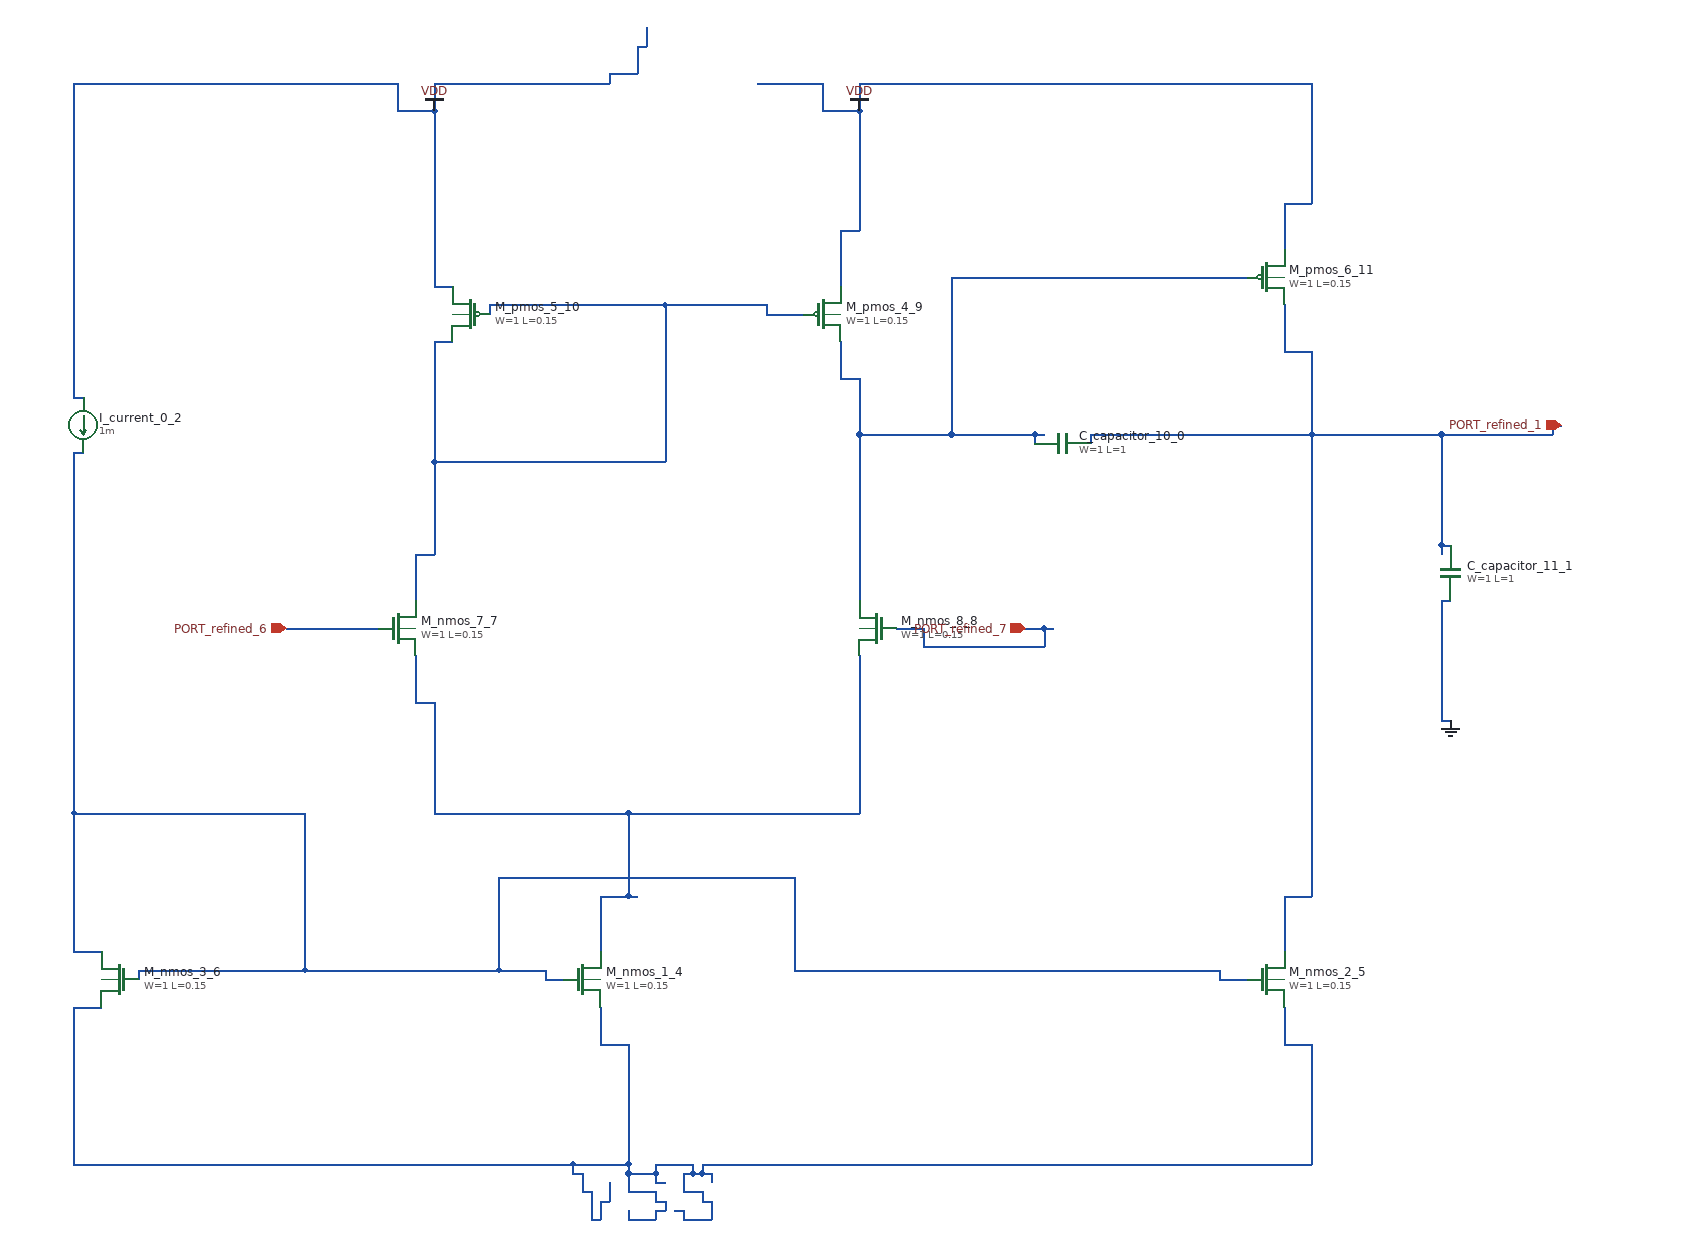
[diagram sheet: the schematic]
v {xschem version=3.4.8 file_version=1.2}
G {}
K {}
V {}
S {}
E {}
C {sky130_fd_pr/cap_mim_m3_1.sym} 1200 500 1 0 {name="C_capacitor_10_0" model=cap_mim_m3_1 W=1 L=1 MF=1 spiceprefix=X}
C {sky130_fd_pr/cap_mim_m3_1.sym} 1620 640 2 0 {name="C_capacitor_11_1" model=cap_mim_m3_1 W=1 L=1 MF=1 spiceprefix=X}
C {devices/isource.sym} 140 480 0 0 {name="I_current_0_2" value=1m}
C {devices/gnd.sym} 1620 800 0 0 {name="l_gnd_9_3" lab="GND"}
C {sky130_fd_pr/nfet3_01v8.sym} 680 1080 0 0 {name="M_nmos_1_4"
W=1
L=0.15
body=GND
nf=1
mult=1
ad="expr('int((@nf + 1)/2) * @W / @nf * 0.29')"
pd="expr('2*int((@nf + 1)/2) * (@W / @nf + 0.29)')"
as="expr('int((@nf + 2)/2) * @W / @nf * 0.29')"
ps="expr('2*int((@nf + 2)/2) * (@W / @nf + 0.29)')"
nrd="expr('0.29 / @W ')" nrs="expr('0.29 / @W ')"
sa=0 sb=0 sd=0
model=nfet_01v8
spiceprefix=X
}
C {sky130_fd_pr/nfet3_01v8.sym} 1420 1080 0 0 {name="M_nmos_2_5"
W=1
L=0.15
body=GND
nf=1
mult=1
ad="expr('int((@nf + 1)/2) * @W / @nf * 0.29')"
pd="expr('2*int((@nf + 1)/2) * (@W / @nf + 0.29)')"
as="expr('int((@nf + 2)/2) * @W / @nf * 0.29')"
ps="expr('2*int((@nf + 2)/2) * (@W / @nf + 0.29)')"
nrd="expr('0.29 / @W ')" nrs="expr('0.29 / @W ')"
sa=0 sb=0 sd=0
model=nfet_01v8
spiceprefix=X
}
C {sky130_fd_pr/nfet3_01v8.sym} 180 1080 0 1 {name="M_nmos_3_6"
W=1
L=0.15
body=GND
nf=1
mult=1
ad="expr('int((@nf + 1)/2) * @W / @nf * 0.29')"
pd="expr('2*int((@nf + 1)/2) * (@W / @nf + 0.29)')"
as="expr('int((@nf + 2)/2) * @W / @nf * 0.29')"
ps="expr('2*int((@nf + 2)/2) * (@W / @nf + 0.29)')"
nrd="expr('0.29 / @W ')" nrs="expr('0.29 / @W ')"
sa=0 sb=0 sd=0
model=nfet_01v8
spiceprefix=X
}
C {sky130_fd_pr/nfet3_01v8.sym} 480 700 0 0 {name="M_nmos_7_7"
W=1
L=0.15
body=GND
nf=1
mult=1
ad="expr('int((@nf + 1)/2) * @W / @nf * 0.29')"
pd="expr('2*int((@nf + 1)/2) * (@W / @nf + 0.29)')"
as="expr('int((@nf + 2)/2) * @W / @nf * 0.29')"
ps="expr('2*int((@nf + 2)/2) * (@W / @nf + 0.29)')"
nrd="expr('0.29 / @W ')" nrs="expr('0.29 / @W ')"
sa=0 sb=0 sd=0
model=nfet_01v8
spiceprefix=X
}
C {sky130_fd_pr/nfet3_01v8.sym} 1000 700 0 1 {name="M_nmos_8_8"
W=1
L=0.15
body=GND
nf=1
mult=1
ad="expr('int((@nf + 1)/2) * @W / @nf * 0.29')"
pd="expr('2*int((@nf + 1)/2) * (@W / @nf + 0.29)')"
as="expr('int((@nf + 2)/2) * @W / @nf * 0.29')"
ps="expr('2*int((@nf + 2)/2) * (@W / @nf + 0.29)')"
nrd="expr('0.29 / @W ')" nrs="expr('0.29 / @W ')"
sa=0 sb=0 sd=0
model=nfet_01v8
spiceprefix=X
}
C {sky130_fd_pr/pfet3_01v8.sym} 940 360 0 0 {name="M_pmos_4_9"
W=1
L=0.15
body=VDD
nf=1
mult=1
ad="expr('int((@nf + 1)/2) * @W / @nf * 0.29')"
pd="expr('2*int((@nf + 1)/2) * (@W / @nf + 0.29)')"
as="expr('int((@nf + 2)/2) * @W / @nf * 0.29')"
ps="expr('2*int((@nf + 2)/2) * (@W / @nf + 0.29)')"
nrd="expr('0.29 / @W ')" nrs="expr('0.29 / @W ')"
sa=0 sb=0 sd=0
model=pfet_01v8
spiceprefix=X
}
C {sky130_fd_pr/pfet3_01v8.sym} 560 360 0 1 {name="M_pmos_5_10"
W=1
L=0.15
body=VDD
nf=1
mult=1
ad="expr('int((@nf + 1)/2) * @W / @nf * 0.29')"
pd="expr('2*int((@nf + 1)/2) * (@W / @nf + 0.29)')"
as="expr('int((@nf + 2)/2) * @W / @nf * 0.29')"
ps="expr('2*int((@nf + 2)/2) * (@W / @nf + 0.29)')"
nrd="expr('0.29 / @W ')" nrs="expr('0.29 / @W ')"
sa=0 sb=0 sd=0
model=pfet_01v8
spiceprefix=X
}
C {sky130_fd_pr/pfet3_01v8.sym} 1420 320 0 0 {name="M_pmos_6_11"
W=1
L=0.15
body=VDD
nf=1
mult=1
ad="expr('int((@nf + 1)/2) * @W / @nf * 0.29')"
pd="expr('2*int((@nf + 1)/2) * (@W / @nf + 0.29)')"
as="expr('int((@nf + 2)/2) * @W / @nf * 0.29')"
ps="expr('2*int((@nf + 2)/2) * (@W / @nf + 0.29)')"
nrd="expr('0.29 / @W ')" nrs="expr('0.29 / @W ')"
sa=0 sb=0 sd=0
model=pfet_01v8
spiceprefix=X
}
C {devices/ipin.sym} 360 700 0 0 {name="p_port_12_12" lab="PORT_refined_6"}
C {devices/ipin.sym} 1740 480 0 0 {name="p_port_13_13" lab="PORT_refined_1"}
C {devices/ipin.sym} 1160 700 0 0 {name="p_port_16_14" lab="PORT_refined_7"}
C {devices/vdd.sym} 520 140 0 0 {name="l_vdd_14_15" lab="VDD"}
C {devices/vdd.sym} 980 140 0 0 {name="l_vdd_15_16" lab="VDD"}
N 980 490 1080 490 {}
N 1080 490 1170 490 {}
N 1170 490 1180 490 {}
N 960 430 980 430 {}
N 1080 320 1400 320 {}
N 960 430 960 390 {}
N 980 670 980 490 {}
N 980 490 980 430 {}
N 1080 490 1080 320 {}
N 1170 500 1170 490 {}
N 1440 990 1470 990 {}
N 1610 610 1620 610 {}
N 1230 490 1470 490 {}
N 1470 490 1610 490 {}
N 1610 490 1730 490 {}
N 1730 480 1740 480 {}
N 1440 400 1470 400 {}
N 1230 500 1230 490 {}
N 1440 1050 1440 990 {}
N 1440 400 1440 350 {}
N 1470 990 1470 490 {}
N 1470 490 1470 400 {}
N 1610 620 1610 610 {}
N 1610 610 1610 490 {}
N 1730 490 1730 480 {}
N 690 1340 700 1340 {}
N 730 1340 760 1340 {}
N 790 1340 820 1340 {}
N 760 1330 770 1330 {}
N 780 1330 790 1330 {}
N 700 1320 710 1320 {}
N 760 1320 770 1320 {}
N 810 1320 820 1320 {}
N 680 1310 690 1310 {}
N 730 1310 760 1310 {}
N 790 1310 810 1310 {}
N 760 1300 770 1300 {}
N 670 1290 680 1290 {}
N 730 1290 760 1290 {}
N 790 1290 800 1290 {}
N 800 1290 810 1290 {}
N 810 1290 820 1290 {}
N 130 1280 670 1280 {}
N 670 1280 730 1280 {}
N 760 1280 800 1280 {}
N 810 1280 1470 1280 {}
N 700 1150 730 1150 {}
N 1440 1150 1470 1150 {}
N 130 1110 160 1110 {}
N 130 1280 130 1110 {}
N 670 1290 670 1280 {}
N 680 1310 680 1290 {}
N 690 1340 690 1310 {}
N 700 1340 700 1320 {}
N 700 1150 700 1110 {}
N 710 1320 710 1300 {}
N 730 1340 730 1330 {}
N 730 1310 730 1290 {}
N 730 1290 730 1280 {}
N 730 1280 730 1150 {}
N 760 1340 760 1330 {}
N 760 1320 760 1310 {}
N 760 1300 760 1290 {}
N 760 1290 760 1280 {}
N 770 1330 770 1320 {}
N 790 1340 790 1330 {}
N 790 1310 790 1290 {}
N 800 1290 800 1280 {}
N 810 1320 810 1310 {}
N 810 1290 810 1280 {}
N 820 1340 820 1320 {}
N 820 1300 820 1290 {}
N 1440 1150 1440 1110 {}
N 1470 1280 1470 1150 {}
N 640 1080 660 1080 {}
N 1370 1080 1400 1080 {}
N 200 1070 380 1070 {}
N 380 1070 590 1070 {}
N 590 1070 640 1070 {}
N 910 1070 1370 1070 {}
N 130 1050 160 1050 {}
N 590 970 910 970 {}
N 130 900 380 900 {}
N 130 510 140 510 {}
N 130 1050 130 900 {}
N 130 900 130 510 {}
N 200 1080 200 1070 {}
N 380 1070 380 900 {}
N 590 1070 590 970 {}
N 640 1080 640 1070 {}
N 910 1070 910 970 {}
N 1370 1080 1370 1070 {}
N 500 620 520 620 {}
N 520 520 770 520 {}
N 520 390 540 390 {}
N 880 360 920 360 {}
N 580 350 770 350 {}
N 770 350 880 350 {}
N 500 670 500 620 {}
N 520 620 520 520 {}
N 520 520 520 390 {}
N 580 360 580 350 {}
N 770 520 770 350 {}
N 880 360 880 350 {}
N 700 990 730 990 {}
N 730 990 740 990 {}
N 520 900 730 900 {}
N 730 900 980 900 {}
N 500 780 520 780 {}
N 500 780 500 730 {}
N 520 900 520 780 {}
N 700 1050 700 990 {}
N 730 990 730 900 {}
N 980 900 980 730 {}
N 360 700 460 700 {}
N 1050 720 1180 720 {}
N 1020 700 1050 700 {}
N 1160 700 1180 700 {}
N 1180 700 1190 700 {}
N 1050 720 1050 700 {}
N 1180 720 1180 700 {}
N 130 450 140 450 {}
N 520 330 540 330 {}
N 960 270 980 270 {}
N 1440 240 1470 240 {}
N 480 140 520 140 {}
N 940 140 980 140 {}
N 130 110 480 110 {}
N 520 110 710 110 {}
N 870 110 940 110 {}
N 980 110 1470 110 {}
N 710 100 740 100 {}
N 740 70 750 70 {}
N 130 450 130 110 {}
N 480 140 480 110 {}
N 520 330 520 140 {}
N 520 140 520 110 {}
N 710 110 710 100 {}
N 740 100 740 70 {}
N 750 70 750 50 {}
N 940 140 940 110 {}
N 960 330 960 270 {}
N 980 270 980 140 {}
N 980 140 980 110 {}
N 1440 290 1440 240 {}
N 1470 240 1470 110 {}
N 1610 800 1620 800 {}
N 1610 670 1620 670 {}
N 1610 800 1610 670 {}
